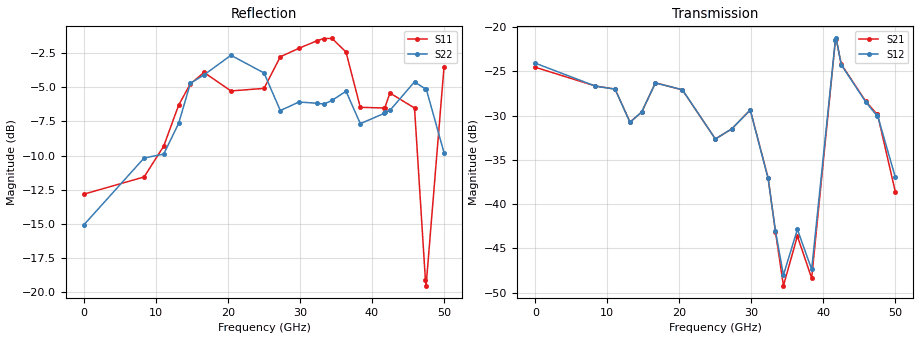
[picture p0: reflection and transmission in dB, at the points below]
!Keysight Technologies,N5245B,MY58422270,A.16.20.02
!Date: Thursday, March 05, 2026 01:31:22
!Correction: S11(C  2-Port  )
!S21(C  2-Port  )
!S12(C  2-Port  )
!S22(C  2-Port  )
!S2P File: Measurements: S11, S21, S12, S22:
# Hz S  dB  R 50
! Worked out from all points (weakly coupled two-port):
!   3201 points, 10 MHz to 50 GHz, reference 50 ohm
!   highest |S21| = -21.32 dB at 41.78 GHz (marker M1); lowest = -49.2 dB at 34.46 GHz (marker M2)
!   lowest |S11| = -19.5 dB at 47.52 GHz (marker M3), VSWR 1.24, Z = 45.3 + j8.89 ohm
!   |S11| at or under -10 dB: start of sweep to 10.11 GHz; 11.36 GHz to 11.92 GHz (565.1 MHz wide, 4.85 % of centre); 46.67 GHz to 48.27 GHz (1.602 GHz wide, 3.37 % of centre)
!   |S22| runs from -19.2 to -2.6 dB; largest |S21 - S12| = 0.0034
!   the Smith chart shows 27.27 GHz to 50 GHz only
!   S11 on the Smith chart (normalised r, x): 27.27 GHz: 0.18, +0.37; 32.33 GHz: 0.42, +1.88; 36.39 GHz: 2.31, -3.27; 42.49 GHz: 0.98, -1.26; 47.42 GHz: 0.85, +0.14; 50 GHz: 0.62, -1.35
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1e7  -12.83 -4.4  -24.53 1.8  -24.07 0.9  -15.07 39.0
8.352081e9  -11.57 174.9  -26.65 28.5  -26.66 28.5  -10.18 -177.0
1.107029e10  -9.31 109.7  -26.99 -71.5  -27.00 -71.7  -9.89 83.6
1.3148e10  -6.30 64.7  -30.72 -127.7  -30.75 -127.9  -7.64 -23.7
1.477267e10  -4.74 12.8  -29.60 -150.1  -29.56 -150.0  -4.70 -91.3
1.667854e10  -3.90 -43.8  -26.28 158.5  -26.30 158.4  -4.08 -141.2
2.041217e10  -5.26 -121.7  -27.08 39.8  -27.06 39.7  -2.64 155.0
2.5005e10  -5.07 179.9  -32.63 -66.0  -32.63 -65.4  -3.94 71.6
2.727017e10  -2.75 138.1  -31.50 -114.6  -31.49 -115.7  -6.70 30.9
2.984778e10  -2.13 93.4  -29.34 158.5  -29.37 157.9  -6.07 -29.1
3.233166e10  -1.58 54.2  -37.04 45.3  -37.09 43.2  -6.16 -104.3
3.334708e10  -1.41 36.0  -43.10 4.4  -43.01 -0.4  -6.22 -126.8
3.445623e10  -1.40 16.3  -49.21 -109.9  -48.01 -109.3  -5.95 -150.3
3.639335e10  -2.41 -23.5  -43.61 117.6  -42.85 116.8  -5.28 173.2
3.837732e10  -6.46 -22.4  -48.36 -94.4  -47.36 -95.9  -7.66 141.2
4.167354e10  -6.51 -52.6  -21.49 -54.2  -21.45 -54.5  -6.91 115.4
4.178289e10  -6.50 -52.5  -21.32 -64.4  -21.26 -64.7  -6.80 114.3
4.248588e10  -5.41 -58.5  -24.18 -116.1  -24.23 -116.7  -6.69 109.8
4.590707e10  -6.51 -117.5  -28.39 50.4  -28.47 50.2  -4.59 62.6
4.742239e10  -19.14 134.2  -29.80 -0.6  -29.98 -1.5  -5.11 43.2
4.751612e10  -19.55 112.8  -29.81 -2.5  -29.94 -2.9  -5.08 42.2
5e10  -3.52 -66.0  -38.61 -142.0  -36.95 -144.5  -9.78 4.0
